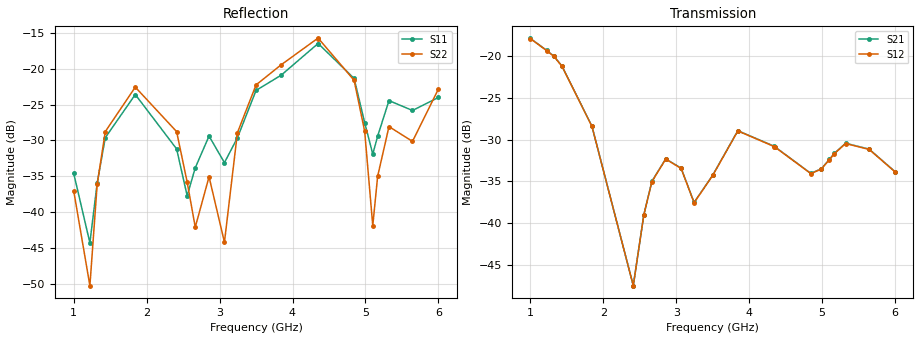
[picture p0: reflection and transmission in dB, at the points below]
!Agilent Technologies,E8364B,MY43040528,A.07.50.67
!Agilent E8364B: A.07.50.67
!Date: Sunday, March 01, 2026 22:19:57
!Correction: S11(Full 2 Port(1,2))
!S21(Full 2 Port(1,2))
!S12(Full 2 Port(1,2))
!S22(Full 2 Port(1,2))
!S2P File: Measurements: S11, S21, S12, S22:
# Hz S  dB  R 50
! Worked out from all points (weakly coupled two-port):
!   451 points, 1 GHz to 6 GHz, reference 50 ohm
!   highest |S21| = -17.87 dB at 1 GHz (marker M1); lowest = -47.5 dB at 2.411 GHz (marker M2)
!   lowest |S11| = -44.3 dB at 1.222 GHz (marker M3), VSWR 1.01, Z = 50.3 - j0.54 ohm
!   |S11| at or under -10 dB: start of sweep to end of sweep
!   |S22| runs from -52.0 to -15.7 dB; largest |S21 - S12| = 0.00044
!   S11 on the Smith chart (normalised r, x): 1 GHz: 1.04, +0.01; 4.356 GHz: 1.20, -0.26; 6 GHz: 0.96, -0.12
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1e9  -34.58 12.7  -17.87 28.6  -17.90 28.7  -37.01 -26.4
1.222222e9  -44.30 -61.8  -19.30 -38.6  -19.33 -38.6  -50.28 101.7
1.322222e9  -35.94 -140.4  -19.99 -71.6  -20.03 -71.5  -36.12 120.0
1.433333e9  -29.61 179.1  -21.19 -109.0  -21.21 -109.0  -28.76 94.3
1.844444e9  -23.58 83.0  -28.40 121.6  -28.42 121.7  -22.55 -12.1
2.411111e9  -31.18 7.4  -47.49 -126.9  -47.50 -127.2  -28.76 -125.9
2.555556e9  -37.72 32.0  -39.00 113.9  -39.03 114.0  -35.81 -147.8
2.666667e9  -33.82 67.1  -34.99 63.3  -35.02 63.4  -42.11 -97.7
2.855556e9  -29.38 47.9  -32.30 -13.0  -32.34 -13.0  -35.07 -98.4
3.066667e9  -33.10 36.5  -33.42 -90.4  -33.45 -90.4  -44.21 -70.2
3.244444e9  -29.62 76.7  -37.53 -133.7  -37.56 -133.6  -28.92 -51.2
3.5e9  -23.01 49.3  -34.26 -154.9  -34.29 -154.9  -22.24 -109.1
3.844444e9  -20.88 19.6  -28.93 87.9  -28.96 87.9  -19.43 -161.6
4.344444e9  -16.51 -44.2  -30.80 -90.9  -30.84 -90.8  -15.74 109.1
4.355556e9  -16.50 -45.9  -30.88 -94.8  -30.91 -94.8  -15.76 106.8
4.844444e9  -21.34 -126.5  -34.04 50.5  -34.07 50.5  -21.60 -0.3
4.988889e9  -27.51 -137.6  -33.49 -30.8  -33.53 -30.7  -28.71 -30.4
5.1e9  -31.90 -100.7  -32.36 -90.7  -32.40 -90.7  -41.90 8.8
5.166667e9  -29.40 -77.6  -31.65 -124.4  -31.69 -124.4  -35.01 63.5
5.322222e9  -24.43 -85.8  -30.43 162.8  -30.47 162.8  -28.06 41.2
5.644444e9  -25.81 -117.1  -31.14 31.2  -31.18 31.2  -30.13 19.6
6e9  -23.99 -104.6  -33.84 -70.2  -33.87 -70.2  -22.81 -5.3
